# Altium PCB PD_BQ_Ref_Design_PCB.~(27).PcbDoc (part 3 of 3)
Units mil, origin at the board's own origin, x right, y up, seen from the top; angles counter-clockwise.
Board outline 2000 x 3000 mil, 4 copper layers (Top Layer, Signal Layer 1, Signal Layer 2, Bottom Layer), stack 61.2 mil thick; 124 components, 53 nets, 359 pads, 494 vias.
Unrouted connection lines stored in the file: 227.

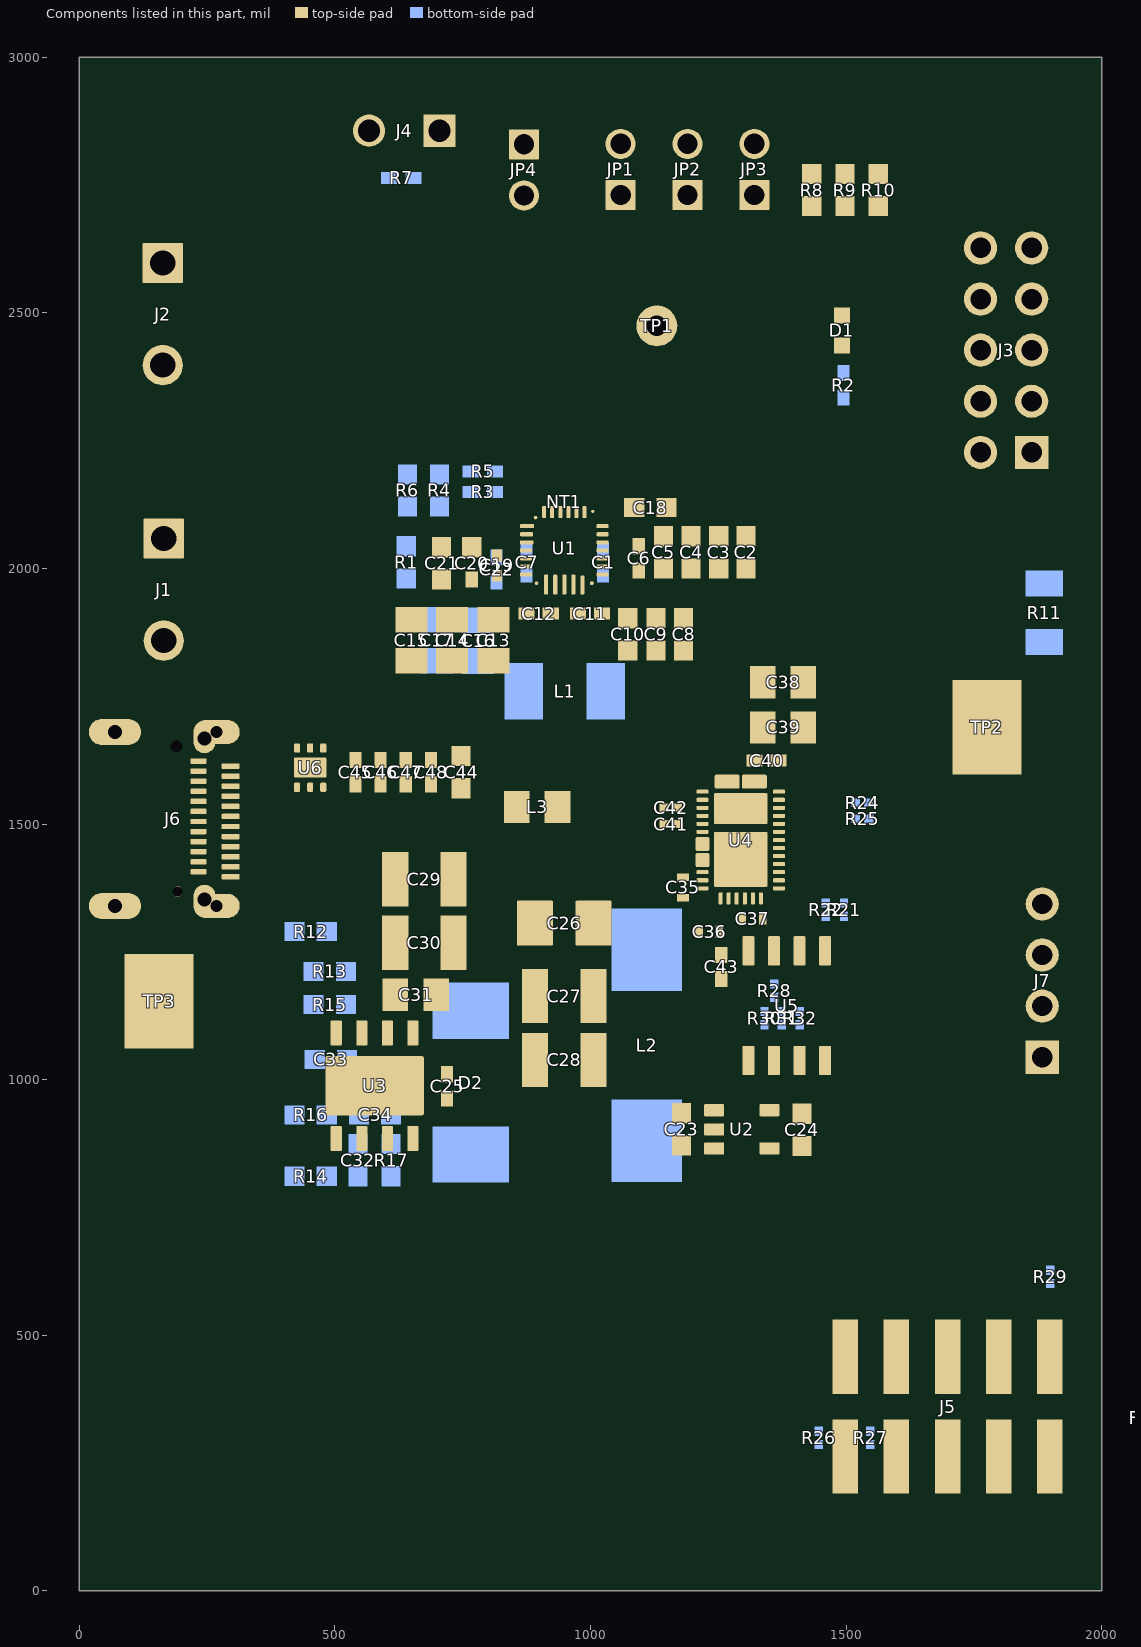
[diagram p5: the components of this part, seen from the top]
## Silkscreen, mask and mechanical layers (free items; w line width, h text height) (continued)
Drill Drawing:
  drawing of 152 lines, arcs and shapes, not listed
  text "Symbol" at 5360.59,3505.96 h72
  text "Quantity" at 5661.16,3505.96 h72
  text "Finished Hole Size" at 5993.16,3505.96 h72
  text "Plated" at 6629.72,3505.96 h72
  text "Hole Type" at 6888.86,3505.96 h72
  text "Drill Layer Pair" at 7264.02,3505.96 h72
  text "Hole Tolerance" at 7988.35,3505.96 h72
  text "1" at 5661.16,3381.64 h60
  text "23.62mil (0.600mm)" at 5993.16,3381.64 h60
  text "NPTH" at 6629.72,3381.64 h60
  text "Round" at 6888.86,3381.64 h60
  text "Top Layer - Bottom Layer" at 7264.02,3381.64 h60
  text "+/-1.18mil" at 7988.35,3381.64 h60
  text "10" at 5661.16,3257.32 h60
  text "7.87mil (0.200mm)" at 5993.16,3257.32 h60
  text "PTH" at 6629.72,3257.32 h60
  text "Round" at 6888.86,3257.32 h60
  text "Top Layer - Bottom Layer" at 7264.02,3257.32 h60
  text "448" at 5661.16,3133 h60
  text "10.00mil (0.254mm)" at 5993.16,3133 h60
  text "PTH" at 6629.72,3133 h60
  text "Round" at 6888.86,3133 h60
  text "Top Layer - Bottom Layer" at 7264.02,3133 h60
  text "24" at 5661.16,3008.68 h60
  text "11.81mil (0.300mm)" at 5993.16,3008.68 h60
  text "PTH" at 6629.72,3008.68 h60
  text "Round" at 6888.86,3008.68 h60
  text "Top Layer - Bottom Layer" at 7264.02,3008.68 h60
  text "12" at 5661.16,2884.36 h60
  text "15.00mil (0.381mm)" at 5993.16,2884.36 h60
  text "PTH" at 6629.72,2884.36 h60
  text "Round" at 6888.86,2884.36 h60
  text "Top Layer - Bottom Layer" at 7264.02,2884.36 h60
  text "4" at 5661.16,2760.04 h60
  text "39.37mil (1.000mm)" at 5993.16,2760.04 h60
  text "PTH" at 6629.72,2760.04 h60
  text "Round" at 6888.86,2760.04 h60
  text "Top Layer - Bottom Layer" at 7264.02,2760.04 h60
  text "19" at 5661.16,2635.72 h60
  text "40.00mil (1.016mm)" at 5993.16,2635.72 h60
  text "PTH" at 6629.72,2635.72 h60
  text "Round" at 6888.86,2635.72 h60
  text "Top Layer - Bottom Layer" at 7264.02,2635.72 h60
  text "2" at 5661.16,2511.4 h60
  text "43.31mil (1.100mm)" at 5993.16,2511.4 h60
  text "PTH" at 6629.72,2511.4 h60
  text "Round" at 6888.86,2511.4 h60
  text "Top Layer - Bottom Layer" at 7264.02,2511.4 h60
  text "4" at 5661.16,2387.08 h60
  text "49.21mil (1.250mm)" at 5993.16,2387.08 h60
  text "PTH" at 6629.72,2387.08 h60
  text "Round" at 6888.86,2387.08 h60
  text "Top Layer - Bottom Layer" at 7264.02,2387.08 h60
  text "4" at 5661.16,2262.76 h60
  text "125.98mil (3.200mm)" at 5993.16,2262.76 h60
  text "PTH" at 6629.72,2262.76 h60
  text "Round" at 6888.86,2262.76 h60
  text "Top Layer - Bottom Layer" at 7264.02,2262.76 h60
  text "1" at 5661.16,2138.44 h60
  text "19.69mil (0.500mm)" at 5993.16,2138.44 h60
  text "NPTH" at 6629.72,2138.44 h60
  text "Slot" at 6888.86,2138.44 h60
  text "Top Layer - Bottom Layer" at 7264.02,2138.44 h60
  text "+/-1.18mil" at 7988.35,2138.44 h60
  text "2" at 5661.16,2014.12 h60
  text "23.62mil (0.600mm)" at 5993.16,2014.12 h60
  text "PTH" at 6629.72,2014.12 h60
  text "Slot" at 6888.86,2014.12 h60
  text "Top Layer - Bottom Layer" at 7264.02,2014.12 h60
  text "+/-1.97mil" at 7988.35,2014.12 h60
  text "2" at 5661.16,1889.8 h60
  text "27.56mil (0.700mm)" at 5993.16,1889.8 h60
  text "PTH" at 6629.72,1889.8 h60
  text "Slot" at 6888.86,1889.8 h60
  text "Top Layer - Bottom Layer" at 7264.02,1889.8 h60
  text "+/-1.97mil" at 7988.35,1889.8 h60
  text "2" at 5661.16,1765.48 h60
  text "27.56mil (0.700mm)" at 5993.16,1765.48 h60
  text "PTH" at 6629.72,1765.48 h60
  text "Slot" at 6888.86,1765.48 h60
  text "Top Layer - Bottom Layer" at 7264.02,1765.48 h60
  text "+/-1.97mil" at 7988.35,1765.48 h60
  text "535 Total" at 5661.16,1641.16 h60
  text "Slot definitions :" at 5360.59,1554.13 h60
  text "Routed Path Length" at 5811.31,1554.13 h60
  text "= Calculated from tool start centre position to tool end centre position." at 6351.05,1554.13 h60
  text "Hole Length" at 5811.31,1504.4 h60
  text "= Routed Path Length + Tool Size = Slot length as defined in the PCB layout" at 6151.24,1504.4 h60
  text ".Layer_Name" at 577,-858.49 h60
M17 Embedded Cavity:
  text ".Layer_Name" at 577,-858.49 h60
M18 Embedded Assembly:
  text ".Layer_Name" at 577,-858.49 h60
M19 Embedded Keepout:
  text ".Layer_Name" at 577,-858.49 h60

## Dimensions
1492.13,2218.5 to 1492.13,765.75 on Top Overlay
386.81,765.75 to 1492.13,765.75 on Top Overlay
0,-400 to 1000,-400 on M2 Board Dimensions
0,0 to 0,3000 on M2 Board Dimensions
0,0 to 2000,0 on M2 Board Dimensions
